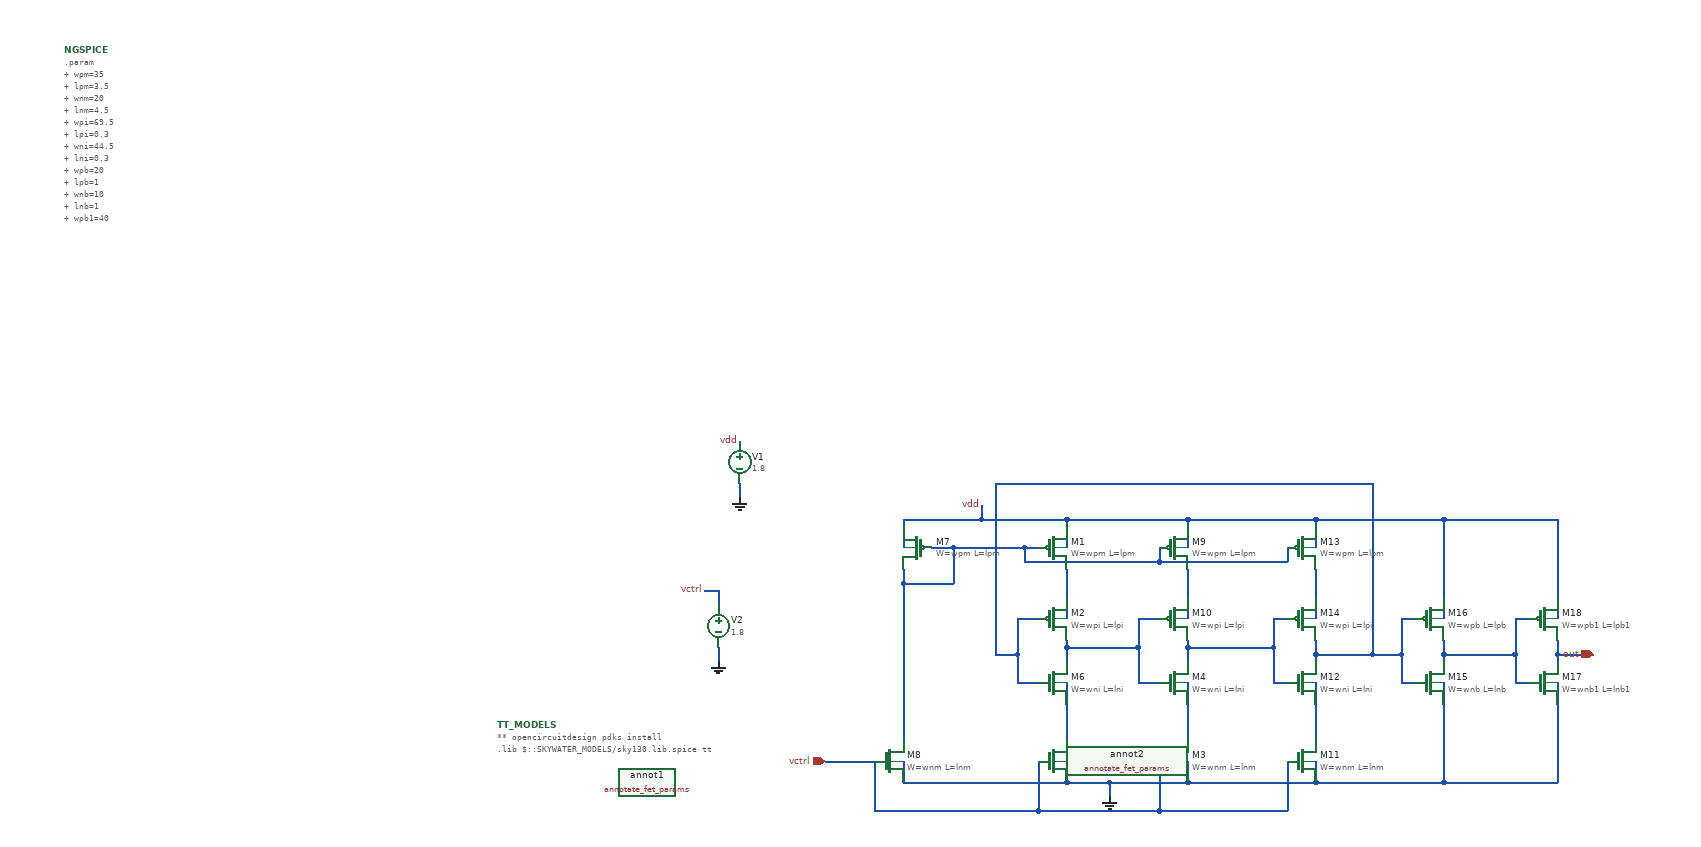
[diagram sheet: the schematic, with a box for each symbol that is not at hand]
v {xschem version=3.4.8RC file_version=1.3}
G {}
K {}
V {}
S {}
F {}
E {}
B 2 1730 -90 2530 310 {flags=graph
y1=-0.23748273
y2=1.9945999
ypos1=0
ypos2=2
divy=5
subdivy=1
unity=1
x1=1.9499922e-06
x2=2.0097598e-06
divx=5
subdivx=1
xlabmag=1.0
ylabmag=1.0
node=out
color=4
dataset=-1
unitx=1
logx=0
logy=0
hilight_wave=0}
N 1440 610 1440 630 {lab=#net1}
N 1440 500 1440 570 {lab=#net2}
N 1370 620 1370 660 {lab=#net3}
N 1370 570 1400 570 {lab=#net3}
N 1380 470 1400 470 {lab=#net4}
N 1210 520 1280 520 {lab=#net4}
N 1280 470 1280 520 {lab=#net4}
N 1400 770 1400 840 {lab=vctrl}
N 1170 770 1170 840 {lab=vctrl}
N 1100 770 1170 770 {lab=vctrl}
N 1210 770 1210 800 {lab=0}
N 1210 800 1440 800 {lab=0}
N 1440 770 1440 800 {lab=0}
N 1370 660 1400 660 {lab=#net3}
N 1210 430 1210 470 {lab=vdd}
N 1320 430 1440 430 {lab=vdd}
N 1440 430 1440 470 {lab=vdd}
N 1610 500 1610 570 {lab=#net5}
N 1570 770 1570 840 {lab=vctrl}
N 1610 770 1610 800 {lab=0}
N 1610 430 1610 470 {lab=vdd}
N 1440 610 1540 610 {lab=#net1}
N 1540 570 1540 610 {lab=#net1}
N 1540 570 1570 570 {lab=#net1}
N 1540 610 1540 660 {lab=#net1}
N 1540 660 1570 660 {lab=#net1}
N 1440 430 1610 430 {lab=vdd}
N 1790 500 1790 570 {lab=#net6}
N 1750 770 1750 840 {lab=vctrl}
N 1790 770 1790 800 {lab=0}
N 1790 430 1790 470 {lab=vdd}
N 1610 610 1730 610 {lab=#net7}
N 1730 570 1730 610 {lab=#net7}
N 1730 570 1750 570 {lab=#net7}
N 1730 610 1730 660 {lab=#net7}
N 1730 660 1750 660 {lab=#net7}
N 1870 620 1910 620 {lab=#net3}
N 1340 380 1340 620 {lab=#net3}
N 1340 620 1370 620 {lab=#net3}
N 1610 800 1790 800 {lab=0}
N 1570 840 1750 840 {lab=vctrl}
N 1210 520 1210 740 {lab=#net4}
N 1320 410 1320 430 {lab=vdd}
N 1610 430 1790 430 {lab=vdd}
N 1440 660 1440 750 {lab=#net8}
N 980 380 980 400 {lab=0}
N 930 530 950 530 {lab=vctrl}
N 950 530 950 550 {lab=vctrl}
N 950 610 950 630 {lab=0}
N 1380 470 1380 490 {lab=#net4}
N 1380 490 1570 490 {lab=#net4}
N 1570 470 1570 490 {lab=#net4}
N 1570 490 1750 490 {lab=#net4}
N 1750 470 1750 490 {lab=#net4}
N 1610 610 1610 630 {lab=#net7}
N 1610 660 1610 750 {lab=#net9}
N 1790 620 1790 630 {lab=#net3}
N 1790 660 1790 750 {lab=#net10}
N 1870 380 1870 620 {lab=#net3}
N 1910 570 1910 620 {lab=#net3}
N 1910 570 1930 570 {lab=#net3}
N 1910 620 1910 660 {lab=#net3}
N 1910 660 1930 660 {lab=#net3}
N 1970 620 1970 630 {lab=#net11}
N 1970 660 1970 800 {lab=0}
N 1970 620 2070 620 {lab=#net11}
N 1970 430 1970 570 {lab=vdd}
N 1790 430 1970 430 {lab=vdd}
N 1340 380 1870 380 {lab=#net3}
N 2070 570 2070 620 {lab=#net11}
N 2070 570 2090 570 {lab=#net11}
N 2070 620 2070 660 {lab=#net11}
N 2070 660 2090 660 {lab=#net11}
N 2130 620 2130 630 {lab=out}
N 2130 660 2130 800 {lab=0}
N 2130 620 2180 620 {lab=out}
N 1970 430 2130 430 {lab=vdd}
N 2130 430 2130 570 {lab=vdd}
N 1970 800 2130 800 {lab=0}
N 1210 500 1210 520 {lab=#net4}
N 1250 470 1280 470 {lab=#net4}
N 1170 840 1400 840 {lab=vctrl}
N 1210 430 1320 430 {lab=vdd}
N 1400 840 1570 840 {lab=vctrl}
N 1500 800 1610 800 {lab=0}
N 1440 600 1440 610 {lab=#net1}
N 1610 600 1610 610 {lab=#net7}
N 1790 600 1790 620 {lab=#net3}
N 1370 570 1370 620 {lab=#net3}
N 1440 800 1500 800 {lab=0}
N 1280 470 1380 470 {lab=#net4}
N 1790 620 1870 620 {lab=#net3}
N 1970 600 1970 620 {lab=#net11}
N 1790 800 1970 800 {lab=0}
N 2130 600 2130 620 {lab=out}
N 1500 800 1500 820 {lab=0}
C {sky130_fd_pr/pfet_01v8.sym} 1230 470 0 1 {name=M7
W="wpm"
L="lpm"
nf=1
mult=1
ad="expr('int((@nf + 1)/2) * @W / @nf * 0.29')"
pd="expr('2*int((@nf + 1)/2) * (@W / @nf + 0.29)')"
as="expr('int((@nf + 2)/2) * @W / @nf * 0.29')"
ps="expr('2*int((@nf + 2)/2) * (@W / @nf + 0.29)')"
nrd="expr('0.29 / @W ')" nrs="expr('0.29 / @W ')"
sa=0 sb=0 sd=0
model=pfet_01v8
spiceprefix=X
}
C {sky130_fd_pr/nfet_01v8.sym} 1190 770 0 0 {name=M8
W="wnm"
L="lnm"
nf=1 
mult=1
ad="expr('int((@nf + 1)/2) * @W / @nf * 0.29')"
pd="expr('2*int((@nf + 1)/2) * (@W / @nf + 0.29)')"
as="expr('int((@nf + 2)/2) * @W / @nf * 0.29')"
ps="expr('2*int((@nf + 2)/2) * (@W / @nf + 0.29)')"
nrd="expr('0.29 / @W ')" nrs="expr('0.29 / @W ')"
sa=0 sb=0 sd=0
model=nfet_01v8
spiceprefix=X
}
C {sky130_fd_pr/nfet_01v8.sym} 1420 770 0 0 {name=M5
W="wnm"
L="lnm"
nf=1 
mult=1
ad="expr('int((@nf + 1)/2) * @W / @nf * 0.29')"
pd="expr('2*int((@nf + 1)/2) * (@W / @nf + 0.29)')"
as="expr('int((@nf + 2)/2) * @W / @nf * 0.29')"
ps="expr('2*int((@nf + 2)/2) * (@W / @nf + 0.29)')"
nrd="expr('0.29 / @W ')" nrs="expr('0.29 / @W ')"
sa=0 sb=0 sd=0
model=nfet_01v8
spiceprefix=X
}
C {sky130_fd_pr/nfet_01v8.sym} 1420 660 0 0 {name=M6
W="wni"
L="lni"
nf=1 
mult=1
ad="expr('int((@nf + 1)/2) * @W / @nf * 0.29')"
pd="expr('2*int((@nf + 1)/2) * (@W / @nf + 0.29)')"
as="expr('int((@nf + 2)/2) * @W / @nf * 0.29')"
ps="expr('2*int((@nf + 2)/2) * (@W / @nf + 0.29)')"
nrd="expr('0.29 / @W ')" nrs="expr('0.29 / @W ')"
sa=0 sb=0 sd=0
model=nfet_01v8
spiceprefix=X
}
C {sky130_fd_pr/pfet_01v8.sym} 1420 470 0 0 {name=M1
W="wpm"
L="lpm"
nf=1
mult=1
ad="expr('int((@nf + 1)/2) * @W / @nf * 0.29')"
pd="expr('2*int((@nf + 1)/2) * (@W / @nf + 0.29)')"
as="expr('int((@nf + 2)/2) * @W / @nf * 0.29')"
ps="expr('2*int((@nf + 2)/2) * (@W / @nf + 0.29)')"
nrd="expr('0.29 / @W ')" nrs="expr('0.29 / @W ')"
sa=0 sb=0 sd=0
model=pfet_01v8
spiceprefix=X
}
C {sky130_fd_pr/pfet_01v8.sym} 1420 570 0 0 {name=M2
W="wpi"
L="lpi"
nf=1
mult=1
ad="expr('int((@nf + 1)/2) * @W / @nf * 0.29')"
pd="expr('2*int((@nf + 1)/2) * (@W / @nf + 0.29)')"
as="expr('int((@nf + 2)/2) * @W / @nf * 0.29')"
ps="expr('2*int((@nf + 2)/2) * (@W / @nf + 0.29)')"
nrd="expr('0.29 / @W ')" nrs="expr('0.29 / @W ')"
sa=0 sb=0 sd=0
model=pfet_01v8
spiceprefix=X
}
C {sky130_fd_pr/nfet_01v8.sym} 1590 770 0 0 {name=M3
W="wnm"
L="lnm"
nf=1 
mult=1
ad="expr('int((@nf + 1)/2) * @W / @nf * 0.29')"
pd="expr('2*int((@nf + 1)/2) * (@W / @nf + 0.29)')"
as="expr('int((@nf + 2)/2) * @W / @nf * 0.29')"
ps="expr('2*int((@nf + 2)/2) * (@W / @nf + 0.29)')"
nrd="expr('0.29 / @W ')" nrs="expr('0.29 / @W ')"
sa=0 sb=0 sd=0
model=nfet_01v8
spiceprefix=X
}
C {sky130_fd_pr/pfet_01v8.sym} 1590 470 0 0 {name=M9
W="wpm"
L="lpm"
nf=1
mult=1
ad="expr('int((@nf + 1)/2) * @W / @nf * 0.29')"
pd="expr('2*int((@nf + 1)/2) * (@W / @nf + 0.29)')"
as="expr('int((@nf + 2)/2) * @W / @nf * 0.29')"
ps="expr('2*int((@nf + 2)/2) * (@W / @nf + 0.29)')"
nrd="expr('0.29 / @W ')" nrs="expr('0.29 / @W ')"
sa=0 sb=0 sd=0
model=pfet_01v8
spiceprefix=X
}
C {sky130_fd_pr/nfet_01v8.sym} 1770 770 0 0 {name=M11
W="wnm"
L="lnm"
nf=1 
mult=1
ad="expr('int((@nf + 1)/2) * @W / @nf * 0.29')"
pd="expr('2*int((@nf + 1)/2) * (@W / @nf + 0.29)')"
as="expr('int((@nf + 2)/2) * @W / @nf * 0.29')"
ps="expr('2*int((@nf + 2)/2) * (@W / @nf + 0.29)')"
nrd="expr('0.29 / @W ')" nrs="expr('0.29 / @W ')"
sa=0 sb=0 sd=0
model=nfet_01v8
spiceprefix=X
}
C {sky130_fd_pr/pfet_01v8.sym} 1770 470 0 0 {name=M13
W="wpm"
L="lpm"
nf=1
mult=1
ad="expr('int((@nf + 1)/2) * @W / @nf * 0.29')"
pd="expr('2*int((@nf + 1)/2) * (@W / @nf + 0.29)')"
as="expr('int((@nf + 2)/2) * @W / @nf * 0.29')"
ps="expr('2*int((@nf + 2)/2) * (@W / @nf + 0.29)')"
nrd="expr('0.29 / @W ')" nrs="expr('0.29 / @W ')"
sa=0 sb=0 sd=0
model=pfet_01v8
spiceprefix=X
}
C {ipin.sym} 1100 770 0 0 {name=p1 lab=vctrl}
C {iopin.sym} 2180 620 0 0 {name=p2 lab=out}
C {code_shown.sym} 30 -230 0 0 {name=NGSPICE only_toplevel=false value="
.param
+ wpm=35
+ lpm=3.5
+ wnm=20
+ lnm=4.5
+ wpi=69.5
+ lpi=0.3
+ wni=44.5
+ lni=0.3
+ wpb=20
+ lpb=1
+ wnb=10
+ lnb=1
+ wpb1=40
+ lpb1=1
+ wnb1=20
+ lnb1=1

.control
    foreach v_val 0.7 1.2
        alter V2 $v_val
        tran 1n 2u
        
        * Measurement logic
        meas tran t_p trig v(out) val=0.9 rise=2 targ v(out) val=0.9 rise=3
        let freq = 1/t_p
        echo For Vctrl = $v_val Frequency = $&freq
    end
.endc
"}
C {gnd.sym} 1500 820 0 0 {name=l2 lab=0}
C {vsource.sym} 980 350 0 0 {name=V1 value=1.8 savecurrent=false}
C {lab_pin.sym} 980 320 0 0 {name=p4 sig_type=std_logic lab=vdd}
C {gnd.sym} 980 400 0 0 {name=l3 lab=0}
C {vsource.sym} 950 580 0 0 {name=V2 value=1.8 savecurrent=false}
C {gnd.sym} 950 630 0 0 {name=l4 lab=0}
C {sky130_fd_pr/nfet_01v8.sym} 1590 660 0 0 {name=M4
W="wni"
L="lni"
nf=1 
mult=1
ad="expr('int((@nf + 1)/2) * @W / @nf * 0.29')"
pd="expr('2*int((@nf + 1)/2) * (@W / @nf + 0.29)')"
as="expr('int((@nf + 2)/2) * @W / @nf * 0.29')"
ps="expr('2*int((@nf + 2)/2) * (@W / @nf + 0.29)')"
nrd="expr('0.29 / @W ')" nrs="expr('0.29 / @W ')"
sa=0 sb=0 sd=0
model=nfet_01v8
spiceprefix=X
}
C {sky130_fd_pr/pfet_01v8.sym} 1590 570 0 0 {name=M10
W="wpi"
L="lpi"
nf=1
mult=1
ad="expr('int((@nf + 1)/2) * @W / @nf * 0.29')"
pd="expr('2*int((@nf + 1)/2) * (@W / @nf + 0.29)')"
as="expr('int((@nf + 2)/2) * @W / @nf * 0.29')"
ps="expr('2*int((@nf + 2)/2) * (@W / @nf + 0.29)')"
nrd="expr('0.29 / @W ')" nrs="expr('0.29 / @W ')"
sa=0 sb=0 sd=0
model=pfet_01v8
spiceprefix=X
}
C {sky130_fd_pr/nfet_01v8.sym} 1770 660 0 0 {name=M12
W="wni"
L="lni"
nf=1 
mult=1
ad="expr('int((@nf + 1)/2) * @W / @nf * 0.29')"
pd="expr('2*int((@nf + 1)/2) * (@W / @nf + 0.29)')"
as="expr('int((@nf + 2)/2) * @W / @nf * 0.29')"
ps="expr('2*int((@nf + 2)/2) * (@W / @nf + 0.29)')"
nrd="expr('0.29 / @W ')" nrs="expr('0.29 / @W ')"
sa=0 sb=0 sd=0
model=nfet_01v8
spiceprefix=X
}
C {sky130_fd_pr/pfet_01v8.sym} 1770 570 0 0 {name=M14
W="wpi"
L="lpi"
nf=1
mult=1
ad="expr('int((@nf + 1)/2) * @W / @nf * 0.29')"
pd="expr('2*int((@nf + 1)/2) * (@W / @nf + 0.29)')"
as="expr('int((@nf + 2)/2) * @W / @nf * 0.29')"
ps="expr('2*int((@nf + 2)/2) * (@W / @nf + 0.29)')"
nrd="expr('0.29 / @W ')" nrs="expr('0.29 / @W ')"
sa=0 sb=0 sd=0
model=pfet_01v8
spiceprefix=X
}
C {lab_pin.sym} 930 530 0 0 {name=p5 sig_type=std_logic lab=vctrl}
C {lab_pin.sym} 1320 410 0 0 {name=p3 sig_type=std_logic lab=vdd}
C {devices/code.sym} 640 720 0 0 {name=TT_MODELS
only_toplevel=true
format="tcleval( @value )"
value="
** opencircuitdesign pdks install
.lib $::SKYWATER_MODELS/sky130.lib.spice tt
"
spice_ignore=false}
C {sky130_fd_pr/annotate_fet_params.sym} 850 800 0 0 {name=annot1 ref=M7}
C {sky130_fd_pr/annotate_fet_params.sym} 940 800 0 0 {name=annot2 ref=M8}
C {sky130_fd_pr/nfet_01v8.sym} 1950 660 0 0 {name=M15
W="wnb"
L="lnb"
nf=1 
mult=1
ad="expr('int((@nf + 1)/2) * @W / @nf * 0.29')"
pd="expr('2*int((@nf + 1)/2) * (@W / @nf + 0.29)')"
as="expr('int((@nf + 2)/2) * @W / @nf * 0.29')"
ps="expr('2*int((@nf + 2)/2) * (@W / @nf + 0.29)')"
nrd="expr('0.29 / @W ')" nrs="expr('0.29 / @W ')"
sa=0 sb=0 sd=0
model=nfet_01v8
spiceprefix=X
}
C {sky130_fd_pr/pfet_01v8.sym} 1950 570 0 0 {name=M16
W="wpb"
L="lpb"
nf=1
mult=1
ad="expr('int((@nf + 1)/2) * @W / @nf * 0.29')"
pd="expr('2*int((@nf + 1)/2) * (@W / @nf + 0.29)')"
as="expr('int((@nf + 2)/2) * @W / @nf * 0.29')"
ps="expr('2*int((@nf + 2)/2) * (@W / @nf + 0.29)')"
nrd="expr('0.29 / @W ')" nrs="expr('0.29 / @W ')"
sa=0 sb=0 sd=0
model=pfet_01v8
spiceprefix=X
}
C {sky130_fd_pr/nfet_01v8.sym} 2110 660 0 0 {name=M17
W="wnb1"
L="lnb1"
nf=1 
mult=1
ad="expr('int((@nf + 1)/2) * @W / @nf * 0.29')"
pd="expr('2*int((@nf + 1)/2) * (@W / @nf + 0.29)')"
as="expr('int((@nf + 2)/2) * @W / @nf * 0.29')"
ps="expr('2*int((@nf + 2)/2) * (@W / @nf + 0.29)')"
nrd="expr('0.29 / @W ')" nrs="expr('0.29 / @W ')"
sa=0 sb=0 sd=0
model=nfet_01v8
spiceprefix=X
}
C {sky130_fd_pr/pfet_01v8.sym} 2110 570 0 0 {name=M18
W="wpb1"
L="lpb1"
nf=1
mult=1
ad="expr('int((@nf + 1)/2) * @W / @nf * 0.29')"
pd="expr('2*int((@nf + 1)/2) * (@W / @nf + 0.29)')"
as="expr('int((@nf + 2)/2) * @W / @nf * 0.29')"
ps="expr('2*int((@nf + 2)/2) * (@W / @nf + 0.29)')"
nrd="expr('0.29 / @W ')" nrs="expr('0.29 / @W ')"
sa=0 sb=0 sd=0
model=pfet_01v8
spiceprefix=X
}
C {launcher.sym} 1520 220 0 0 {name=h5
descr="load waves"
tclcommand="xschem raw_read $netlist_dir/vco_tb.raw tran"
}
